VERSION 5.7 ;
  NOWIREEXTENSIONATPIN ON ;
  DIVIDERCHAR "/" ;
  BUSBITCHARS "[]" ;
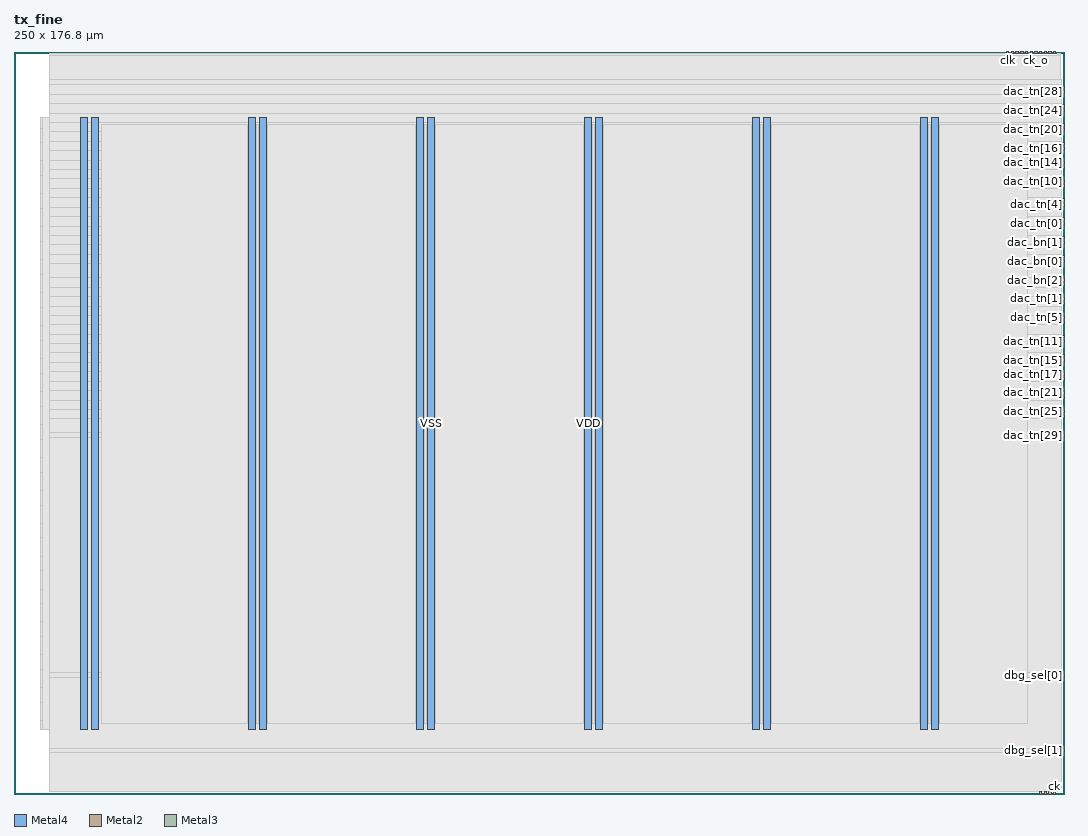
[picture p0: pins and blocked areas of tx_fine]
MACRO tx_fine
  CLASS BLOCK ;
  FOREIGN tx_fine ;
  ORIGIN 0.000 0.000 ;
  SIZE 250.000 BY 176.800 ;
  PIN VDD
    DIRECTION INOUT ;
    USE POWER ;
    PORT
      LAYER Metal4 ;
        RECT 15.920 15.380 17.520 161.020 ;
    END
    PORT
      LAYER Metal4 ;
        RECT 55.920 15.380 57.520 161.020 ;
    END
    PORT
      LAYER Metal4 ;
        RECT 95.920 15.380 97.520 161.020 ;
    END
    PORT
      LAYER Metal4 ;
        RECT 135.920 15.380 137.520 161.020 ;
    END
    PORT
      LAYER Metal4 ;
        RECT 175.920 15.380 177.520 161.020 ;
    END
    PORT
      LAYER Metal4 ;
        RECT 215.920 15.380 217.520 161.020 ;
    END
  END VDD
  PIN VSS
    DIRECTION INOUT ;
    USE GROUND ;
    PORT
      LAYER Metal4 ;
        RECT 18.520 15.380 20.120 161.020 ;
    END
    PORT
      LAYER Metal4 ;
        RECT 58.520 15.380 60.120 161.020 ;
    END
    PORT
      LAYER Metal4 ;
        RECT 98.520 15.380 100.120 161.020 ;
    END
    PORT
      LAYER Metal4 ;
        RECT 138.520 15.380 140.120 161.020 ;
    END
    PORT
      LAYER Metal4 ;
        RECT 178.520 15.380 180.120 161.020 ;
    END
    PORT
      LAYER Metal4 ;
        RECT 218.520 15.380 220.120 161.020 ;
    END
  END VSS
  PIN ck
    DIRECTION INPUT ;
    USE SIGNAL ;
    ANTENNAGATEAREA 2.366000 ;
    ANTENNADIFFAREA 0.820800 ;
    PORT
      LAYER Metal2 ;
        RECT 247.520 0.000 248.080 0.560 ;
    END
  END ck
  PIN ck_o
    DIRECTION OUTPUT ;
    USE SIGNAL ;
    ANTENNADIFFAREA 0.897600 ;
    PORT
      LAYER Metal2 ;
        RECT 243.040 176.240 243.600 176.800 ;
    END
  END ck_o
  PIN clk
    DIRECTION INPUT ;
    USE SIGNAL ;
    ANTENNAGATEAREA 2.366000 ;
    ANTENNADIFFAREA 0.820800 ;
    PORT
      LAYER Metal2 ;
        RECT 236.320 176.240 236.880 176.800 ;
    END
  END clk
  PIN cs_n
    DIRECTION INPUT ;
    USE SIGNAL ;
    ANTENNAGATEAREA 0.498500 ;
    ANTENNADIFFAREA 0.410400 ;
    PORT
      LAYER Metal2 ;
        RECT 241.920 176.240 242.480 176.800 ;
    END
  END cs_n
  PIN dac_bn[0]
    DIRECTION OUTPUT ;
    USE SIGNAL ;
    ANTENNADIFFAREA 0.897600 ;
    PORT
      LAYER Metal3 ;
        RECT 249.440 126.560 250.000 127.120 ;
    END
  END dac_bn[0]
  PIN dac_bn[1]
    DIRECTION OUTPUT ;
    USE SIGNAL ;
    ANTENNADIFFAREA 0.897600 ;
    PORT
      LAYER Metal3 ;
        RECT 249.440 131.040 250.000 131.600 ;
    END
  END dac_bn[1]
  PIN dac_bn[2]
    DIRECTION OUTPUT ;
    USE SIGNAL ;
    ANTENNADIFFAREA 0.897600 ;
    PORT
      LAYER Metal3 ;
        RECT 249.440 122.080 250.000 122.640 ;
    END
  END dac_bn[2]
  PIN dac_bn[3]
    DIRECTION OUTPUT ;
    USE SIGNAL ;
    ANTENNADIFFAREA 0.897600 ;
    PORT
      LAYER Metal3 ;
        RECT 249.440 132.160 250.000 132.720 ;
    END
  END dac_bn[3]
  PIN dac_bn[4]
    DIRECTION OUTPUT ;
    USE SIGNAL ;
    ANTENNADIFFAREA 0.897600 ;
    PORT
      LAYER Metal3 ;
        RECT 249.440 120.960 250.000 121.520 ;
    END
  END dac_bn[4]
  PIN dac_sdn
    DIRECTION OUTPUT ;
    USE SIGNAL ;
    ANTENNADIFFAREA 0.897600 ;
    PORT
      LAYER Metal3 ;
        RECT 249.440 127.680 250.000 128.240 ;
    END
  END dac_sdn
  PIN dac_tn[0]
    DIRECTION OUTPUT ;
    USE SIGNAL ;
    ANTENNADIFFAREA 0.897600 ;
    PORT
      LAYER Metal3 ;
        RECT 249.440 135.520 250.000 136.080 ;
    END
  END dac_tn[0]
  PIN dac_tn[10]
    DIRECTION OUTPUT ;
    USE SIGNAL ;
    ANTENNADIFFAREA 0.897600 ;
    PORT
      LAYER Metal3 ;
        RECT 249.440 145.600 250.000 146.160 ;
    END
  END dac_tn[10]
  PIN dac_tn[11]
    DIRECTION OUTPUT ;
    USE SIGNAL ;
    ANTENNADIFFAREA 0.897600 ;
    PORT
      LAYER Metal3 ;
        RECT 249.440 107.520 250.000 108.080 ;
    END
  END dac_tn[11]
  PIN dac_tn[12]
    DIRECTION OUTPUT ;
    USE SIGNAL ;
    ANTENNADIFFAREA 0.897600 ;
    PORT
      LAYER Metal3 ;
        RECT 249.440 148.960 250.000 149.520 ;
    END
  END dac_tn[12]
  PIN dac_tn[13]
    DIRECTION OUTPUT ;
    USE SIGNAL ;
    ANTENNADIFFAREA 0.897600 ;
    PORT
      LAYER Metal3 ;
        RECT 249.440 104.160 250.000 104.720 ;
    END
  END dac_tn[13]
  PIN dac_tn[14]
    DIRECTION OUTPUT ;
    USE SIGNAL ;
    ANTENNADIFFAREA 0.897600 ;
    PORT
      LAYER Metal3 ;
        RECT 249.440 150.080 250.000 150.640 ;
    END
  END dac_tn[14]
  PIN dac_tn[15]
    DIRECTION OUTPUT ;
    USE SIGNAL ;
    ANTENNADIFFAREA 0.897600 ;
    PORT
      LAYER Metal3 ;
        RECT 249.440 103.040 250.000 103.600 ;
    END
  END dac_tn[15]
  PIN dac_tn[16]
    DIRECTION OUTPUT ;
    USE SIGNAL ;
    ANTENNADIFFAREA 0.897600 ;
    PORT
      LAYER Metal3 ;
        RECT 249.440 153.440 250.000 154.000 ;
    END
  END dac_tn[16]
  PIN dac_tn[17]
    DIRECTION OUTPUT ;
    USE SIGNAL ;
    ANTENNADIFFAREA 0.897600 ;
    PORT
      LAYER Metal3 ;
        RECT 249.440 99.680 250.000 100.240 ;
    END
  END dac_tn[17]
  PIN dac_tn[18]
    DIRECTION OUTPUT ;
    USE SIGNAL ;
    ANTENNADIFFAREA 0.897600 ;
    PORT
      LAYER Metal3 ;
        RECT 249.440 154.560 250.000 155.120 ;
    END
  END dac_tn[18]
  PIN dac_tn[19]
    DIRECTION OUTPUT ;
    USE SIGNAL ;
    ANTENNADIFFAREA 0.897600 ;
    PORT
      LAYER Metal3 ;
        RECT 249.440 98.560 250.000 99.120 ;
    END
  END dac_tn[19]
  PIN dac_tn[1]
    DIRECTION OUTPUT ;
    USE SIGNAL ;
    ANTENNADIFFAREA 0.897600 ;
    PORT
      LAYER Metal3 ;
        RECT 249.440 117.600 250.000 118.160 ;
    END
  END dac_tn[1]
  PIN dac_tn[20]
    DIRECTION OUTPUT ;
    USE SIGNAL ;
    ANTENNADIFFAREA 0.897600 ;
    PORT
      LAYER Metal3 ;
        RECT 249.440 157.920 250.000 158.480 ;
    END
  END dac_tn[20]
  PIN dac_tn[21]
    DIRECTION OUTPUT ;
    USE SIGNAL ;
    ANTENNADIFFAREA 0.897600 ;
    PORT
      LAYER Metal3 ;
        RECT 249.440 95.200 250.000 95.760 ;
    END
  END dac_tn[21]
  PIN dac_tn[22]
    DIRECTION OUTPUT ;
    USE SIGNAL ;
    ANTENNADIFFAREA 0.897600 ;
    PORT
      LAYER Metal3 ;
        RECT 249.440 159.040 250.000 159.600 ;
    END
  END dac_tn[22]
  PIN dac_tn[23]
    DIRECTION OUTPUT ;
    USE SIGNAL ;
    ANTENNADIFFAREA 0.897600 ;
    PORT
      LAYER Metal3 ;
        RECT 249.440 94.080 250.000 94.640 ;
    END
  END dac_tn[23]
  PIN dac_tn[24]
    DIRECTION OUTPUT ;
    USE SIGNAL ;
    ANTENNADIFFAREA 0.897600 ;
    PORT
      LAYER Metal3 ;
        RECT 249.440 162.400 250.000 162.960 ;
    END
  END dac_tn[24]
  PIN dac_tn[25]
    DIRECTION OUTPUT ;
    USE SIGNAL ;
    ANTENNADIFFAREA 0.897600 ;
    PORT
      LAYER Metal3 ;
        RECT 249.440 90.720 250.000 91.280 ;
    END
  END dac_tn[25]
  PIN dac_tn[26]
    DIRECTION OUTPUT ;
    USE SIGNAL ;
    ANTENNADIFFAREA 0.897600 ;
    PORT
      LAYER Metal3 ;
        RECT 249.440 163.520 250.000 164.080 ;
    END
  END dac_tn[26]
  PIN dac_tn[27]
    DIRECTION OUTPUT ;
    USE SIGNAL ;
    ANTENNADIFFAREA 0.897600 ;
    PORT
      LAYER Metal3 ;
        RECT 249.440 89.600 250.000 90.160 ;
    END
  END dac_tn[27]
  PIN dac_tn[28]
    DIRECTION OUTPUT ;
    USE SIGNAL ;
    ANTENNADIFFAREA 0.897600 ;
    PORT
      LAYER Metal3 ;
        RECT 249.440 166.880 250.000 167.440 ;
    END
  END dac_tn[28]
  PIN dac_tn[29]
    DIRECTION OUTPUT ;
    USE SIGNAL ;
    ANTENNADIFFAREA 0.897600 ;
    PORT
      LAYER Metal3 ;
        RECT 249.440 85.120 250.000 85.680 ;
    END
  END dac_tn[29]
  PIN dac_tn[2]
    DIRECTION OUTPUT ;
    USE SIGNAL ;
    ANTENNADIFFAREA 0.897600 ;
    PORT
      LAYER Metal3 ;
        RECT 249.440 136.640 250.000 137.200 ;
    END
  END dac_tn[2]
  PIN dac_tn[30]
    DIRECTION OUTPUT ;
    USE SIGNAL ;
    ANTENNADIFFAREA 0.897600 ;
    PORT
      LAYER Metal3 ;
        RECT 249.440 168.000 250.000 168.560 ;
    END
  END dac_tn[30]
  PIN dac_tn[3]
    DIRECTION OUTPUT ;
    USE SIGNAL ;
    ANTENNADIFFAREA 0.897600 ;
    PORT
      LAYER Metal3 ;
        RECT 249.440 116.480 250.000 117.040 ;
    END
  END dac_tn[3]
  PIN dac_tn[4]
    DIRECTION OUTPUT ;
    USE SIGNAL ;
    ANTENNADIFFAREA 0.897600 ;
    PORT
      LAYER Metal3 ;
        RECT 249.440 140.000 250.000 140.560 ;
    END
  END dac_tn[4]
  PIN dac_tn[5]
    DIRECTION OUTPUT ;
    USE SIGNAL ;
    ANTENNADIFFAREA 0.897600 ;
    PORT
      LAYER Metal3 ;
        RECT 249.440 113.120 250.000 113.680 ;
    END
  END dac_tn[5]
  PIN dac_tn[6]
    DIRECTION OUTPUT ;
    USE SIGNAL ;
    ANTENNADIFFAREA 0.897600 ;
    PORT
      LAYER Metal3 ;
        RECT 249.440 141.120 250.000 141.680 ;
    END
  END dac_tn[6]
  PIN dac_tn[7]
    DIRECTION OUTPUT ;
    USE SIGNAL ;
    ANTENNADIFFAREA 0.897600 ;
    PORT
      LAYER Metal3 ;
        RECT 249.440 112.000 250.000 112.560 ;
    END
  END dac_tn[7]
  PIN dac_tn[8]
    DIRECTION OUTPUT ;
    USE SIGNAL ;
    ANTENNADIFFAREA 0.897600 ;
    PORT
      LAYER Metal3 ;
        RECT 249.440 144.480 250.000 145.040 ;
    END
  END dac_tn[8]
  PIN dac_tn[9]
    DIRECTION OUTPUT ;
    USE SIGNAL ;
    ANTENNADIFFAREA 0.897600 ;
    PORT
      LAYER Metal3 ;
        RECT 249.440 108.640 250.000 109.200 ;
    END
  END dac_tn[9]
  PIN dbg_sel[0]
    DIRECTION OUTPUT ;
    USE SIGNAL ;
    ANTENNADIFFAREA 0.897600 ;
    PORT
      LAYER Metal3 ;
        RECT 249.440 28.000 250.000 28.560 ;
    END
  END dbg_sel[0]
  PIN dbg_sel[1]
    DIRECTION OUTPUT ;
    USE SIGNAL ;
    ANTENNADIFFAREA 0.897600 ;
    PORT
      LAYER Metal3 ;
        RECT 249.440 10.080 250.000 10.640 ;
    END
  END dbg_sel[1]
  PIN dbg_sel[2]
    DIRECTION OUTPUT ;
    USE SIGNAL ;
    ANTENNADIFFAREA 0.897600 ;
    PORT
      LAYER Metal2 ;
        RECT 245.280 0.000 245.840 0.560 ;
    END
  END dbg_sel[2]
  PIN dbg_sel[3]
    DIRECTION OUTPUT ;
    USE SIGNAL ;
    ANTENNADIFFAREA 0.897600 ;
    PORT
      LAYER Metal2 ;
        RECT 244.160 0.000 244.720 0.560 ;
    END
  END dbg_sel[3]
  PIN div1024
    DIRECTION OUTPUT ;
    USE SIGNAL ;
    ANTENNADIFFAREA 0.897600 ;
    PORT
      LAYER Metal2 ;
        RECT 246.400 176.240 246.960 176.800 ;
    END
  END div1024
  PIN div16
    DIRECTION OUTPUT ;
    USE SIGNAL ;
    ANTENNADIFFAREA 0.897600 ;
    PORT
      LAYER Metal2 ;
        RECT 244.160 176.240 244.720 176.800 ;
    END
  END div16
  PIN div64
    DIRECTION OUTPUT ;
    USE SIGNAL ;
    ANTENNADIFFAREA 0.897600 ;
    PORT
      LAYER Metal2 ;
        RECT 245.280 176.240 245.840 176.800 ;
    END
  END div64
  PIN fsk
    DIRECTION INPUT ;
    USE SIGNAL ;
    ANTENNAGATEAREA 0.498500 ;
    ANTENNADIFFAREA 0.410400 ;
    PORT
      LAYER Metal2 ;
        RECT 238.560 176.240 239.120 176.800 ;
    END
  END fsk
  PIN miso
    DIRECTION OUTPUT ;
    USE SIGNAL ;
    ANTENNADIFFAREA 0.897600 ;
    PORT
      LAYER Metal2 ;
        RECT 247.520 176.240 248.080 176.800 ;
    END
  END miso
  PIN mosi
    DIRECTION INPUT ;
    USE SIGNAL ;
    ANTENNAGATEAREA 0.498500 ;
    ANTENNADIFFAREA 0.410400 ;
    PORT
      LAYER Metal2 ;
        RECT 240.800 176.240 241.360 176.800 ;
    END
  END mosi
  PIN rst_n
    DIRECTION INPUT ;
    USE SIGNAL ;
    ANTENNAGATEAREA 1.102000 ;
    ANTENNADIFFAREA 0.410400 ;
    PORT
      LAYER Metal2 ;
        RECT 237.440 176.240 238.000 176.800 ;
    END
  END rst_n
  PIN rx_en
    DIRECTION OUTPUT ;
    USE SIGNAL ;
    ANTENNADIFFAREA 0.897600 ;
    PORT
      LAYER Metal2 ;
        RECT 246.400 0.000 246.960 0.560 ;
    END
  END rx_en
  PIN sclk
    DIRECTION INPUT ;
    USE SIGNAL ;
    ANTENNAGATEAREA 0.498500 ;
    ANTENNADIFFAREA 0.410400 ;
    PORT
      LAYER Metal2 ;
        RECT 239.680 176.240 240.240 176.800 ;
    END
  END sclk
  OBS
      LAYER Nwell ;
        RECT 6.290 158.560 243.470 161.150 ;
      LAYER Pwell ;
        RECT 6.290 155.040 243.470 158.560 ;
      LAYER Nwell ;
        RECT 6.290 150.720 243.470 155.040 ;
      LAYER Pwell ;
        RECT 6.290 147.200 243.470 150.720 ;
      LAYER Nwell ;
        RECT 6.290 142.880 243.470 147.200 ;
      LAYER Pwell ;
        RECT 6.290 139.360 243.470 142.880 ;
      LAYER Nwell ;
        RECT 6.290 135.040 243.470 139.360 ;
      LAYER Pwell ;
        RECT 6.290 131.520 243.470 135.040 ;
      LAYER Nwell ;
        RECT 6.290 127.200 243.470 131.520 ;
      LAYER Pwell ;
        RECT 6.290 123.680 243.470 127.200 ;
      LAYER Nwell ;
        RECT 6.290 119.360 243.470 123.680 ;
      LAYER Pwell ;
        RECT 6.290 115.840 243.470 119.360 ;
      LAYER Nwell ;
        RECT 6.290 111.520 243.470 115.840 ;
      LAYER Pwell ;
        RECT 6.290 108.000 243.470 111.520 ;
      LAYER Nwell ;
        RECT 6.290 103.680 243.470 108.000 ;
      LAYER Pwell ;
        RECT 6.290 100.160 243.470 103.680 ;
      LAYER Nwell ;
        RECT 6.290 95.840 243.470 100.160 ;
      LAYER Pwell ;
        RECT 6.290 92.320 243.470 95.840 ;
      LAYER Nwell ;
        RECT 6.290 88.000 243.470 92.320 ;
      LAYER Pwell ;
        RECT 6.290 84.480 243.470 88.000 ;
      LAYER Nwell ;
        RECT 6.290 80.160 243.470 84.480 ;
      LAYER Pwell ;
        RECT 6.290 76.640 243.470 80.160 ;
      LAYER Nwell ;
        RECT 6.290 72.320 243.470 76.640 ;
      LAYER Pwell ;
        RECT 6.290 68.800 243.470 72.320 ;
      LAYER Nwell ;
        RECT 6.290 64.480 243.470 68.800 ;
      LAYER Pwell ;
        RECT 6.290 60.960 243.470 64.480 ;
      LAYER Nwell ;
        RECT 6.290 56.640 243.470 60.960 ;
      LAYER Pwell ;
        RECT 6.290 53.120 243.470 56.640 ;
      LAYER Nwell ;
        RECT 6.290 48.800 243.470 53.120 ;
      LAYER Pwell ;
        RECT 6.290 45.280 243.470 48.800 ;
      LAYER Nwell ;
        RECT 6.290 40.960 243.470 45.280 ;
      LAYER Pwell ;
        RECT 6.290 37.440 243.470 40.960 ;
      LAYER Nwell ;
        RECT 6.290 33.120 243.470 37.440 ;
      LAYER Pwell ;
        RECT 6.290 29.600 243.470 33.120 ;
      LAYER Nwell ;
        RECT 6.290 25.280 243.470 29.600 ;
      LAYER Pwell ;
        RECT 6.290 21.760 243.470 25.280 ;
      LAYER Nwell ;
        RECT 6.290 17.440 243.470 21.760 ;
      LAYER Pwell ;
        RECT 6.290 15.250 243.470 17.440 ;
      LAYER Metal1 ;
        RECT 6.720 15.380 243.040 161.020 ;
      LAYER Metal2 ;
        RECT 8.540 175.940 236.020 176.240 ;
        RECT 248.380 175.940 249.060 176.240 ;
        RECT 8.540 0.860 249.060 175.940 ;
        RECT 8.540 0.560 243.860 0.860 ;
        RECT 248.380 0.560 249.060 0.860 ;
      LAYER Metal3 ;
        RECT 8.490 168.860 249.440 170.100 ;
        RECT 8.490 166.580 249.140 168.860 ;
        RECT 8.490 164.380 249.440 166.580 ;
        RECT 8.490 162.100 249.140 164.380 ;
        RECT 8.490 159.900 249.440 162.100 ;
        RECT 8.490 157.620 249.140 159.900 ;
        RECT 8.490 155.420 249.440 157.620 ;
        RECT 8.490 153.140 249.140 155.420 ;
        RECT 8.490 150.940 249.440 153.140 ;
        RECT 8.490 148.660 249.140 150.940 ;
        RECT 8.490 146.460 249.440 148.660 ;
        RECT 8.490 144.180 249.140 146.460 ;
        RECT 8.490 141.980 249.440 144.180 ;
        RECT 8.490 139.700 249.140 141.980 ;
        RECT 8.490 137.500 249.440 139.700 ;
        RECT 8.490 135.220 249.140 137.500 ;
        RECT 8.490 133.020 249.440 135.220 ;
        RECT 8.490 130.740 249.140 133.020 ;
        RECT 8.490 128.540 249.440 130.740 ;
        RECT 8.490 126.260 249.140 128.540 ;
        RECT 8.490 122.940 249.440 126.260 ;
        RECT 8.490 120.660 249.140 122.940 ;
        RECT 8.490 118.460 249.440 120.660 ;
        RECT 8.490 116.180 249.140 118.460 ;
        RECT 8.490 113.980 249.440 116.180 ;
        RECT 8.490 111.700 249.140 113.980 ;
        RECT 8.490 109.500 249.440 111.700 ;
        RECT 8.490 107.220 249.140 109.500 ;
        RECT 8.490 105.020 249.440 107.220 ;
        RECT 8.490 102.740 249.140 105.020 ;
        RECT 8.490 100.540 249.440 102.740 ;
        RECT 8.490 98.260 249.140 100.540 ;
        RECT 8.490 96.060 249.440 98.260 ;
        RECT 8.490 93.780 249.140 96.060 ;
        RECT 8.490 91.580 249.440 93.780 ;
        RECT 8.490 89.300 249.140 91.580 ;
        RECT 8.490 85.980 249.440 89.300 ;
        RECT 8.490 84.820 249.140 85.980 ;
        RECT 8.490 28.860 249.440 84.820 ;
        RECT 8.490 27.700 249.140 28.860 ;
        RECT 8.490 10.940 249.440 27.700 ;
        RECT 8.490 9.780 249.140 10.940 ;
        RECT 8.490 0.700 249.440 9.780 ;
      LAYER Metal4 ;
        RECT 20.860 16.890 55.620 159.510 ;
        RECT 57.820 16.890 58.220 159.510 ;
        RECT 60.420 16.890 95.620 159.510 ;
        RECT 97.820 16.890 98.220 159.510 ;
        RECT 100.420 16.890 135.620 159.510 ;
        RECT 137.820 16.890 138.220 159.510 ;
        RECT 140.420 16.890 175.620 159.510 ;
        RECT 177.820 16.890 178.220 159.510 ;
        RECT 180.420 16.890 215.620 159.510 ;
        RECT 217.820 16.890 218.220 159.510 ;
        RECT 220.420 16.890 241.220 159.510 ;
  END
END tx_fine
END LIBRARY

